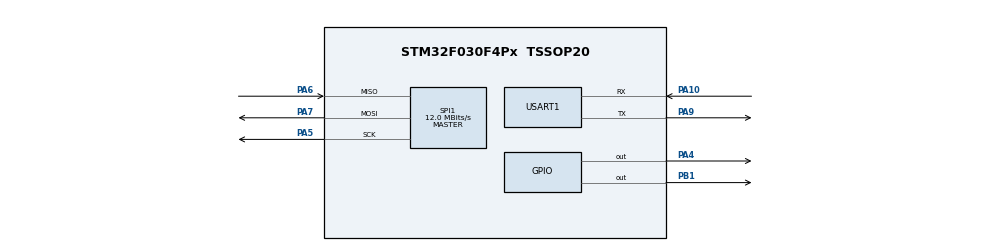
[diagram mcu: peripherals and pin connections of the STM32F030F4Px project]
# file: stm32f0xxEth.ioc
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Mcu.Family=STM32F0
Mcu.Name=STM32F030F4Px
Mcu.Package=TSSOP20
PA10.Mode=Asynchronous
PA10.Signal=USART1_RX
PA13.Mode=Serial_Wire
PA13.Signal=SYS_SWDIO
PA14.Mode=Serial_Wire
PA14.Signal=SYS_SWCLK
PA4.Signal=GPIO_Output
PA5.GPIO_PuPd=GPIO_NOPULL
PA5.Mode=Full_Duplex_Master
PA5.Signal=SPI1_SCK
PA6.GPIO_PuPd=GPIO_NOPULL
PA6.Mode=Full_Duplex_Master
PA6.Signal=SPI1_MISO
PA7.GPIO_PuPd=GPIO_NOPULL
PA7.Mode=Full_Duplex_Master
PA7.Signal=SPI1_MOSI
PA9.Mode=Asynchronous
PA9.Signal=USART1_TX
PB1.Signal=GPIO_Output
PF0-OSC_IN.Mode=HSE-External-Oscillator
PF0-OSC_IN.Signal=RCC_OSC_IN
PF1-OSC_OUT.Mode=HSE-External-Oscillator
PF1-OSC_OUT.Signal=RCC_OSC_OUT
ProjectManager.HeapSize=0x200
ProjectManager.StackSize=0x400
ProjectManager.TargetToolchain=SW4STM32
RCC.AHBFreq_Value=48000000
RCC.APB1Freq_Value=48000000
RCC.APB1TimFreq_Value=48000000
RCC.HCLKFreq_Value=48000000
RCC.PLLMUL=RCC_PLL_MUL6
RCC.PLLSourceVirtual=RCC_PLLSOURCE_HSE
RCC.SYSCLKFreq_VALUE=48000000
RCC.SYSCLKSource=RCC_SYSCLKSOURCE_PLLCLK
SPI1.BaudRatePrescaler=SPI_BAUDRATEPRESCALER_4
SPI1.CalculateBaudRate=12.0 MBits/s
SPI1.DataSize=SPI_DATASIZE_8BIT
SPI1.Direction=SPI_DIRECTION_2LINES
SPI1.Mode=SPI_MODE_MASTER
SPI1.VirtualType=VM_MASTER
USART1.VirtualMode-Asynchronous=VM_ASYNC
board=stm32f0xxEth

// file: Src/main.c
/**
  ******************************************************************************
  * File Name          : main.c
  * Description        : Main program body
  ******************************************************************************
  ** This notice applies to any and all portions of this file
  * that are not between comment pairs USER CODE BEGIN and
  * USER CODE END. Other portions of this file, whether
  * inserted by the user or by software development tools
  * are owned by their respective copyright owners.
  *
  * COPYRIGHT(c) 2017 STMicroelectronics
  *
  * Redistribution and use in source and binary forms, with or without modification,
  * are permitted provided that the following conditions are met:
  *   1. Redistributions of source code must retain the above copyright notice,
  *      this list of conditions and the following disclaimer.
  *   2. Redistributions in binary form must reproduce the above copyright notice,
  *      this list of conditions and the following disclaimer in the documentation
  *      and/or other materials provided with the distribution.
  *   3. Neither the name of STMicroelectronics nor the names of its contributors
  *      may be used to endorse or promote products derived from this software
  *      without specific prior written permission.
  *
  * THIS SOFTWARE IS PROVIDED BY THE COPYRIGHT HOLDERS AND CONTRIBUTORS "AS IS"
  * AND ANY EXPRESS OR IMPLIED WARRANTIES, INCLUDING, BUT NOT LIMITED TO, THE
  * IMPLIED WARRANTIES OF MERCHANTABILITY AND FITNESS FOR A PARTICULAR PURPOSE ARE
  * DISCLAIMED. IN NO EVENT SHALL THE COPYRIGHT HOLDER OR CONTRIBUTORS BE LIABLE
  * FOR ANY DIRECT, INDIRECT, INCIDENTAL, SPECIAL, EXEMPLARY, OR CONSEQUENTIAL
  * DAMAGES (INCLUDING, BUT NOT LIMITED TO, PROCUREMENT OF SUBSTITUTE GOODS OR
  * SERVICES; LOSS OF USE, DATA, OR PROFITS; OR BUSINESS INTERRUPTION) HOWEVER
  * CAUSED AND ON ANY THEORY OF LIABILITY, WHETHER IN CONTRACT, STRICT LIABILITY,
  * OR TORT (INCLUDING NEGLIGENCE OR OTHERWISE) ARISING IN ANY WAY OUT OF THE USE
  * OF THIS SOFTWARE, EVEN IF ADVISED OF THE POSSIBILITY OF SUCH DAMAGE.
  *
  ******************************************************************************
  */
#include "main.h"
#include "stm32f0xx_hal.h"

/* USER CODE BEGIN Includes */
#include "string.h"
#include "EtherShield.h"

/* USER CODE END Includes */

SPI_HandleTypeDef hspi1;

UART_HandleTypeDef huart1;

/* USER CODE BEGIN PV */
/* Private variables ---------------------------------------------------------*/
#define NET_BUF_SIZE (1<<10)
//#define PING

uint8_t mymac[6] = { 0xf0, 0xd4, 0xa2, 0x9b, 0x12, 0x20 };
uint8_t  ip[]  = {192,  168, 10, 52};
uint8_t  dip[]  = {192,  168, 10, 15};
/* USER CODE END PV */

void SystemClock_Config(void);
static void MX_GPIO_Init(void);
static void MX_SPI1_Init(void);
static void MX_USART1_UART_Init(void);

/* USER CODE BEGIN PFP */
/* Private function prototypes -----------------------------------------------*/
void print(unsigned char* str){
	HAL_UART_Transmit(&huart1, str, strlen(str),900);
}

void printINT(uint8_t str){
	uint8_t table[8];
	sprintf (table, "%d", str);
	HAL_UART_Transmit(&huart1, table, strlen(table),100);
}

uint32_t getUs(void) {
uint32_t usTicks = HAL_RCC_GetSysClockFreq() / 1000000;
register uint32_t ms, cycle_cnt;
do {
ms = HAL_GetTick();
cycle_cnt = SysTick->VAL;
} while (ms != HAL_GetTick());
return (ms * 900) + (usTicks * 900 - cycle_cnt) / usTicks;
}

void delayUs(uint16_t micros) {
uint32_t start = getUs();
while (getUs()-start < (uint32_t) micros) {
asm("nop");
}
}

uint16_t get_udp_data_len(uint8_t *buf)
{
	int16_t i;
	i=(((int16_t)buf[IP_TOTLEN_H_P])<<8)|(buf[IP_TOTLEN_L_P]&0xff);
	i-=IP_HEADER_LEN;
	i-=8;
	if (i<=0){
		i=0;
	}
	return((uint16_t)i);
}

uint8_t net_sendbuf[NET_BUF_SIZE + 1];

/* USER CODE END PFP */

int main(void)
{

  /* MCU Configuration----------------------------------------------------------*/

  /* Reset of all peripherals, Initializes the Flash interface and the Systick. */
  HAL_Init();

  /* Configure the system clock */
  SystemClock_Config();

  /* Initialize all configured peripherals */
  MX_GPIO_Init();
  MX_SPI1_Init();
  MX_USART1_UART_Init();

  /* USER CODE BEGIN 2 */

//  print("Test Komunikacji \r\n");
//  print("\r\n");
  enc28j60_set_spi(&hspi1);
  ES_enc28j60Init(mymac);
  ES_init_ip_arp_udp_tcp(mymac, ip, 80);

  //ES_enc28j60PacketSend(42,ARP_req);

  print("\r\n Zainicjowalem enc28j60! \r\n");
  uint8_t enc28j60_rev = ES_enc28j60Revision();
  printINT(enc28j60_rev);
  print("<>\r\n");

  static uint8_t net_buf[NET_BUF_SIZE + 1];
  static uint8_t netanswer_buf[NET_BUF_SIZE + 1];
  static uint16_t info_data_len = 0;
  uint8_t buf[1024];
  /* USER CODE END 2 */

  /* Infinite loop */
  /* USER CODE BEGIN WHILE */

 // uint8_t  remote_mac[] = {0x00, 0x00, 0x00, 0x00, 0x00, 0x00};
 // uint8_t  remote_mac[] = {0xf8, 0xd1, 0x11, 0x03, 0x3b, 0x34};

  uint8_t  remote_ip[]  = {192,  168, 10, 15};

  unsigned char ARP_req[] = {0xFF, 0xFF, 0xFF, 0xFF, 0xFF, 0xFF, 0xAC, 0x22,   0x0B, 0x51, 0x7A, 0xEF, 0x08, 0x06, 0x00, 0x01,
		  	  	  	  	  	 0x08, 0x00, 0x06, 0x04, 0x00, 0x01, 0xAC, 0x22,   0x0B, 0x51, 0x7A, 0xEF, 0xC0, 0xA8, 0x01, 0x02,
							 0x00, 0x00, 0x00, 0x00, 0x00, 0x00, 0xC0, 0xA8,   0x01, 0x01};

  unsigned char buff[128];

  while (1)
  {
  /* USER CODE END WHILE */

  /* USER CODE BEGIN 3 */
//#define UDP_LOOP
#ifdef UDP_LOOP
	    uint16_t dat_p;
		dat_p = packetloop_icmp_udp(net_buf, ES_enc28j60PacketReceive(NET_BUF_SIZE, net_buf));
		if (dat_p != 0) {
			memcpy(buf, &net_buf[dat_p], info_data_len);
			print(buf);
			make_udp_reply_from_request(net_buf, (char *)buf, info_data_len, 23);
		}
#endif

#ifdef PING

	  while(1)
		{
			packetloop_icmp_udp(net_sendbuf, ES_enc28j60PacketReceive(NET_BUF_SIZE, net_sendbuf));
		}
#endif

	  uint8_t data[] = "Hello world!!";
	  //ES_send_udp_data1(data, 15, 80, dip, 80);
	 // ES_send_udp_data2(buff, remote_mac, 14, 26525, remote_ip, 36401);
	  ES_send_udp_data1(buff, (sizeof data)-1, 26525, remote_ip, 36401, data);

	  //ES_send_udp_data2(net_sendbuf, remote_mac, (3+channels)*sizeof(*net_senddata), 26524, remote_ip, 36400);
	  HAL_GPIO_TogglePin(GPIOA, GPIO_PIN_4);
	  //unsigned char buff[42];
	  //client_arp_whohas(buff, remote_ip);

	  HAL_Delay(3000);
	  //enc28j60PacketSend(42,ARP_req);
  }
  /* USER CODE END 3 */

}

/** System Clock Configuration
*/
void SystemClock_Config(void)
{

  RCC_OscInitTypeDef RCC_OscInitStruct;
  RCC_ClkInitTypeDef RCC_ClkInitStruct;
  RCC_PeriphCLKInitTypeDef PeriphClkInit;

    /**Initializes the CPU, AHB and APB busses clocks
    */
  RCC_OscInitStruct.OscillatorType = RCC_OSCILLATORTYPE_HSI;
  RCC_OscInitStruct.HSIState = RCC_HSI_ON;
  RCC_OscInitStruct.HSICalibrationValue = 16;
  RCC_OscInitStruct.PLL.PLLState = RCC_PLL_NONE;
  if (HAL_RCC_OscConfig(&RCC_OscInitStruct) != HAL_OK)
  {
    _Error_Handler(__FILE__, __LINE__);
  }

    /**Initializes the CPU, AHB and APB busses clocks
    */
  RCC_ClkInitStruct.ClockType = RCC_CLOCKTYPE_HCLK|RCC_CLOCKTYPE_SYSCLK
                              |RCC_CLOCKTYPE_PCLK1;
  RCC_ClkInitStruct.SYSCLKSource = RCC_SYSCLKSOURCE_HSI;
  RCC_ClkInitStruct.AHBCLKDivider = RCC_SYSCLK_DIV1;
  RCC_ClkInitStruct.APB1CLKDivider = RCC_HCLK_DIV1;

  if (HAL_RCC_ClockConfig(&RCC_ClkInitStruct, FLASH_LATENCY_0) != HAL_OK)
  {
    _Error_Handler(__FILE__, __LINE__);
  }

  PeriphClkInit.PeriphClockSelection = RCC_PERIPHCLK_USART1;
  PeriphClkInit.Usart1ClockSelection = RCC_USART1CLKSOURCE_PCLK1;
  if (HAL_RCCEx_PeriphCLKConfig(&PeriphClkInit) != HAL_OK)
  {
    _Error_Handler(__FILE__, __LINE__);
  }

    /**Configure the Systick interrupt time
    */
  HAL_SYSTICK_Config(HAL_RCC_GetHCLKFreq()/1000);

    /**Configure the Systick
    */
  HAL_SYSTICK_CLKSourceConfig(SYSTICK_CLKSOURCE_HCLK);

  /* SysTick_IRQn interrupt configuration */
  HAL_NVIC_SetPriority(SysTick_IRQn, 0, 0);
}

/* SPI1 init function */
static void MX_SPI1_Init(void)
{

  hspi1.Instance = SPI1;
  hspi1.Init.Mode = SPI_MODE_MASTER;
  hspi1.Init.Direction = SPI_DIRECTION_2LINES;
  hspi1.Init.DataSize = SPI_DATASIZE_8BIT;
  hspi1.Init.CLKPolarity = SPI_POLARITY_LOW;
  hspi1.Init.CLKPhase = SPI_PHASE_1EDGE;
  hspi1.Init.NSS = SPI_NSS_SOFT;
  hspi1.Init.BaudRatePrescaler = SPI_BAUDRATEPRESCALER_2;
  hspi1.Init.FirstBit = SPI_FIRSTBIT_MSB;
  hspi1.Init.TIMode = SPI_TIMODE_DISABLE;
  hspi1.Init.CRCCalculation = SPI_CRCCALCULATION_DISABLE;
  hspi1.Init.CRCPolynomial = 7;
  hspi1.Init.CRCLength = SPI_CRC_LENGTH_DATASIZE;
  hspi1.Init.NSSPMode = SPI_NSS_PULSE_ENABLE;
  if (HAL_SPI_Init(&hspi1) != HAL_OK)
  {
    _Error_Handler(__FILE__, __LINE__);
  }

}

/* USART1 init function */
static void MX_USART1_UART_Init(void)
{

  huart1.Instance = USART1;
  huart1.Init.BaudRate = 38400;
  huart1.Init.WordLength = UART_WORDLENGTH_8B;
  huart1.Init.StopBits = UART_STOPBITS_1;
  huart1.Init.Parity = UART_PARITY_NONE;
  huart1.Init.Mode = UART_MODE_TX_RX;
  huart1.Init.HwFlowCtl = UART_HWCONTROL_NONE;
  huart1.Init.OverSampling = UART_OVERSAMPLING_16;
  huart1.Init.OneBitSampling = UART_ONE_BIT_SAMPLE_DISABLE;
  huart1.AdvancedInit.AdvFeatureInit = UART_ADVFEATURE_NO_INIT;
  if (HAL_UART_Init(&huart1) != HAL_OK)
  {
    _Error_Handler(__FILE__, __LINE__);
  }

}

/** Configure pins as
        * Analog
        * Input
        * Output
        * EVENT_OUT
        * EXTI
*/
static void MX_GPIO_Init(void)
{

  GPIO_InitTypeDef GPIO_InitStruct;

  /* GPIO Ports Clock Enable */
  __HAL_RCC_GPIOA_CLK_ENABLE();
  __HAL_RCC_GPIOB_CLK_ENABLE();

  /*Configure GPIO pin Output Level */
  HAL_GPIO_WritePin(GPIOA, GPIO_PIN_4, GPIO_PIN_RESET);

  /*Configure GPIO pin Output Level */
  HAL_GPIO_WritePin(GPIOB, GPIO_PIN_1, GPIO_PIN_RESET);

  /*Configure GPIO pin : PA4 */
  GPIO_InitStruct.Pin = GPIO_PIN_4;
  GPIO_InitStruct.Mode = GPIO_MODE_OUTPUT_PP;
  GPIO_InitStruct.Pull = GPIO_NOPULL;
  GPIO_InitStruct.Speed = GPIO_SPEED_FREQ_LOW;
  HAL_GPIO_Init(GPIOA, &GPIO_InitStruct);

  /*Configure GPIO pin : PB1 */
  GPIO_InitStruct.Pin = GPIO_PIN_1;
  GPIO_InitStruct.Mode = GPIO_MODE_OUTPUT_PP;
  GPIO_InitStruct.Pull = GPIO_NOPULL;
  GPIO_InitStruct.Speed = GPIO_SPEED_FREQ_LOW;
  HAL_GPIO_Init(GPIOB, &GPIO_InitStruct);

}

void _Error_Handler(char * file, int line)
{
  while(1)
  {
  }
}

/************************ (C) COPYRIGHT STMicroelectronics *****END OF FILE****/
